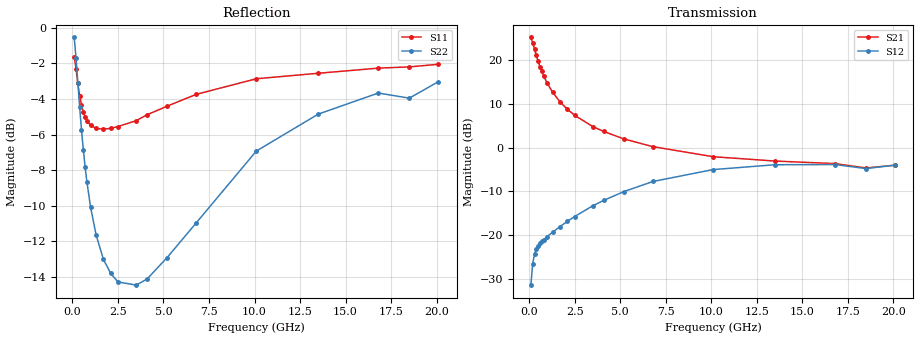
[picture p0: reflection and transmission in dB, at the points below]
!  Infineon Technologies AG
! BFR380L3 , PF131585-7, No.6, Th 09.10.01, soldered on pcb-board, measured with PP GSG850
!  Vce=3.5 V,  Ic=6.0 mA
! Common Emitter S-Parameters:  15. November 2001
#  GHz  S  MA  R  50
! f  S11  S21  S12  S22
! GHz  Mag  Ang  Mag  Ang  Mag  Ang  Mag  Ang
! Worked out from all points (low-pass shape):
!   201 points, 100 MHz to 20.1 GHz, reference 50 ohm
!   highest |S21| = 25.14 dB at 100 MHz (marker M1); lowest = -4.7 dB at 18.5 GHz (marker M2)
!   |S21| within 3 dB of the highest: start of sweep to 322.8 MHz
!   lowest |S11| = -5.7 dB at 1.7 GHz (marker M3), VSWR 3.16, Z = 15.9 - j1.4 ohm
!   |S11| at or under -10 dB: nowhere
!   |S22| runs from -14.6 to -0.5 dB; largest |S21 - S12| = 18
!   S11 on the Smith chart (normalised r, x): 100 MHz: 1.21, -3.23; 400 MHz: 0.37, -0.82; 1 GHz: 0.33, -0.24; 4.1 GHz: 0.31, +0.36; 10.1 GHz: 0.40, +1.16; 20.1 GHz: 0.97, +2.54
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0.1  0.8272 -30.7  18.07 159.6  0.02693 73.2  0.9393 -18.6
0.2  0.7678 -57.6  15.67 142.7  0.04714 62.1  0.8232 -33.8
0.3  0.6975 -79.5  13.28 130.0  0.06093 54.3  0.7001 -44.7
0.4  0.645 -96.4  11.26 120.4  0.06944 49.1  0.5971 -52.5
0.5  0.607 -110.1  9.646 113.0  0.07581 46.3  0.517 -58.2
0.6  0.5801 -121.0  8.377 107.3  0.08081 44.8  0.455 -62.3
0.7  0.5605 -130.1  7.39 102.5  0.08519 44.2  0.4064 -65.6
0.8  0.5473 -137.6  6.588 98.4  0.08893 44.1  0.3682 -68.2
1  0.532 -149.7  5.411 91.7  0.09661 44.6  0.3134 -72.4
1.3  0.5216 -163.2  4.258 83.8  0.1084 46.5  0.2622 -77.4
1.7  0.5189 -176.4  3.325 75.1  0.1253 48.8  0.224 -83.3
2.1  0.5217 173.0  2.737 67.7  0.1436 50.7  0.2044 -89.4
2.5  0.5278 164.3  2.337 61.0  0.163 51.6  0.1934 -95.9
3.5  0.5481 146.3  1.735 46.3  0.2166 51.7  0.1894 -113.7
4.1  0.5696 137.5  1.526 38.8  0.2495 50.5  0.197 -126.8
5.2  0.6021 123.3  1.256 26.2  0.314 45.5  0.2263 -147.5
6.8  0.65 104.9  1.023 11.5  0.4099 36.9  0.2832 -177.5
10.1  0.7189 78.0  0.7862 -8.1  0.5601 14.6  0.4505 137.8
13.5  0.7449 59.8  0.7014 -22.2  0.6366 -7.8  0.572 103.9
16.8  0.77 47.5  0.6559 -33.3  0.6399 -24.7  0.6556 80.0
18.5  0.7762 45.7  0.585 -40.4  0.5754 -33.3  0.6342 73.6
20.1  0.7895 38.5  0.6289 -44.1  0.6294 -38.6  0.7056 62.6
